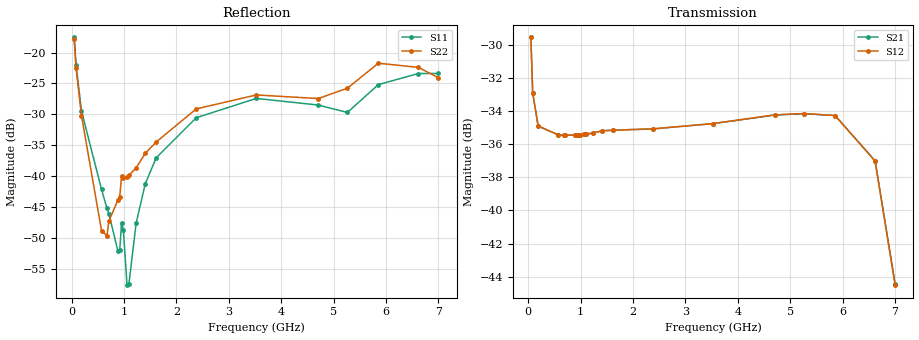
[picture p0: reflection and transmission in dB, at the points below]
! Integrated Device Technology
! Corporate Headquarters
! 6024 Silver Creek Valley Road
! San Jose, CA 95138  USA
! Phone:  1-408-284-8200
! Toll Free:  1-800-223-1366
! Webpage:  http://www.idt.com/
! Timing and RF Division
! 515 Groton Road, Suite 102
! Westford, MA 01886-6024
! Device:  F2258
! Description: Voltage Variable RF Attenuator
! Frequency:  50.0 -  6000.00 MHz
! Package:  3x3 mm Thin QFN Plastic Package: 16 pin
! Ports:  2 RF, 2 DC
!  Pin  1  = NC
!  Pin  2  = NC
!  Pin  3  = RF2  = Port 2
!  Pin  4  = GND
!  Pin  5  = Vdd
!  Pin  6  = NC
!  Pin  7  = VCTRL
!  Pin  8  = NC
!  Pin  9  = GND
!  Pin 10  = RF1  = Port 1
!  Pin 11  = NC
!  Pin 12  = NC
!  Pin 13  = NC
!  Pin 14  = NC
!  Pin 15  = NC
!  Pin 16  = NC
! Vcntrl:  2.280 Volts
! Vdd:  +3.300 Volts
! Current:  1.149 mA
! Data:  The device was measured on a the F2258 evaluation board which has
!  individual transmission lines to the RF pins.  Data was collected
!  using a calibrated network analyzer.  The evaluation board was
!  de-embedded using a TRL calibration technique.
!  The reference plane is the edge of the package pin.
! Misc:  SN 10
!  Action Tracker AT0285
! Date Measured:  2014-12-10
! Date:  2016-01-13  MJV
! Note:
!  Integrated Device Technology supplies this data as a sample of measured
!  data at the package pin for this product.  Your particular data for this
!  product may vary.
!  Data was taken at 25 degrees C.
!  Integrated Device Technology reserves the right to change this data at anytime.
!Freq_(GHz)  S11M_(dB)  S11P_(deg)  S21M_(dB)  S21P_(deg)  S12M_(dB)  S12P_(deg)  S22M_(dB)  S22P_(deg)
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# GHz S dB R 50
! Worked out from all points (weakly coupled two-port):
!   201 points, 50 MHz to 7 GHz, reference 50 ohm
!   highest |S21| = -29.52 dB at 50 MHz (marker M1); lowest = -44.4 dB at 7 GHz (marker M2)
!   lowest |S11| = -57.5 dB at 1.058 GHz (marker M3), VSWR 1.00, Z = 49.9 + j0.057 ohm
!   |S11| at or under -10 dB: start of sweep to end of sweep
!   |S22| runs from -49.9 to -17.8 dB; largest |S21 - S12| = 8.7e-05
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0.05  -17.56 -111.0  -29.52 -68.5  -29.52 -68.4  -17.85 -111.3
0.08475  -21.98 -107.4  -32.88 -48.7  -32.88 -48.7  -22.52 -107.5
0.189  -29.42 -109.5  -34.89 -24.7  -34.88 -24.7  -30.17 -109.6
0.57125  -42.10 -124.9  -35.42 -10.3  -35.42 -10.3  -48.75 -163.7
0.6755  -45.16 -132.1  -35.44 -9.4  -35.44 -9.4  -49.59 144.9
0.71025  -45.99 -137.7  -35.44 -9.2  -35.44 -9.2  -47.24 134.8
0.884  -52.04 166.5  -35.43 -8.4  -35.43 -8.4  -43.82 117.2
0.91875  -51.85 149.9  -35.43 -8.3  -35.43 -8.3  -43.33 115.1
0.9535  -47.51 -162.5  -35.44 -8.2  -35.44 -8.2  -39.87 121.7
0.98825  -48.67 -174.4  -35.42 -8.1  -35.42 -8.1  -40.19 119.4
1.05775  -57.54 154.5  -35.40 -7.9  -35.40 -8.0  -40.06 104.9
1.0925  -57.43 120.3  -35.39 -7.9  -35.38 -7.9  -39.83 100.8
1.2315  -47.56 47.3  -35.31 -7.9  -35.31 -7.9  -38.63 79.0
1.40525  -41.19 33.8  -35.18 -8.5  -35.18 -8.5  -36.27 65.9
1.61375  -37.00 32.9  -35.14 -9.6  -35.14 -9.6  -34.45 53.2
2.37825  -30.53 48.2  -35.06 -13.2  -35.06 -13.2  -29.10 43.3
3.525  -27.41 91.7  -34.74 -19.6  -34.74 -19.6  -26.85 67.5
4.7065  -28.48 95.6  -34.22 -28.7  -34.21 -28.7  -27.43 58.7
5.2625  -29.67 54.5  -34.14 -34.9  -34.13 -34.9  -25.76 21.4
5.85325  -25.18 29.8  -34.25 -45.5  -34.25 -45.5  -21.73 -2.5
6.61775  -23.39 49.7  -36.99 -68.6  -37.01 -68.7  -22.40 -44.3
7  -23.38 84.5  -44.45 -61.7  -44.52 -61.0  -24.07 -129.9
